One B-rep face of a CAD part: STEP entity #1449.
In plain terms, the planar face has unit normal (0, 1, 0).
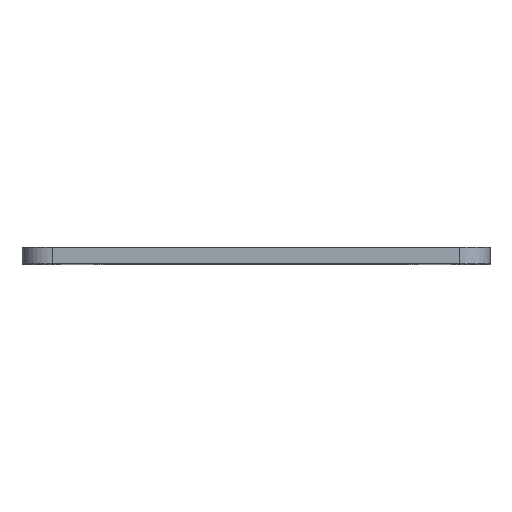
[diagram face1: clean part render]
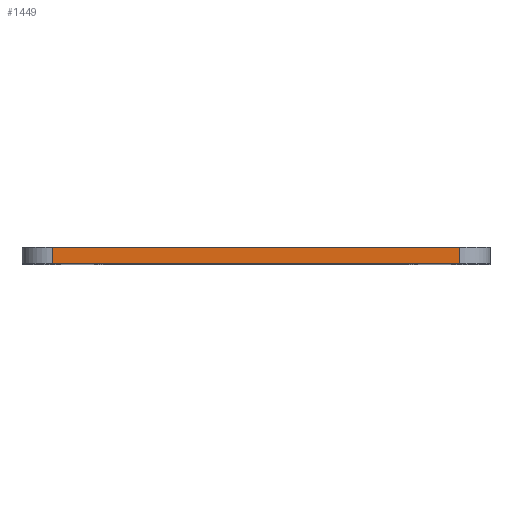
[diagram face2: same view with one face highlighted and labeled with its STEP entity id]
Its self-contained STEP definition (entity closure, numbers rounded to 3 decimals):
#62 = PLANE('',#63);
#63 = AXIS2_PLACEMENT_3D('',#64,#65,#66);
#64 = CARTESIAN_POINT('',(0.,14.5,-1.2));
#65 = DIRECTION('',(0.,0.,1.));
#66 = DIRECTION('',(1.,0.,-0.));
#118 = PLANE('',#119);
#119 = AXIS2_PLACEMENT_3D('',#120,#121,#122);
#120 = CARTESIAN_POINT('',(0.,14.5,0.));
#121 = DIRECTION('',(0.,0.,1.));
#122 = DIRECTION('',(1.,0.,-0.));
#385 = VERTEX_POINT('',#386);
#386 = CARTESIAN_POINT('',(14.8,30.,-1.2));
#405 = CYLINDRICAL_SURFACE('',#406,2.2);
#406 = AXIS2_PLACEMENT_3D('',#407,#408,#409);
#407 = CARTESIAN_POINT('',(14.8,27.8,-1.2));
#408 = DIRECTION('',(0.,0.,-1.));
#409 = DIRECTION('',(-1.,0.,0.));
#417 = EDGE_CURVE('',#418,#385,#420,.T.);
#418 = VERTEX_POINT('',#419);
#419 = CARTESIAN_POINT('',(-14.8,30.,-1.2));
#420 = SURFACE_CURVE('',#421,(#425,#432),.PCURVE_S1.);
#421 = LINE('',#422,#423);
#422 = CARTESIAN_POINT('',(0.,30.,-1.2));
#423 = VECTOR('',#424,1.);
#424 = DIRECTION('',(1.,0.,0.));
#425 = PCURVE('',#62,#426);
#426 = DEFINITIONAL_REPRESENTATION('',(#427),#431);
#427 = LINE('',#428,#429);
#428 = CARTESIAN_POINT('',(0.,15.5));
#429 = VECTOR('',#430,1.);
#430 = DIRECTION('',(1.,0.));
#431 = ( GEOMETRIC_REPRESENTATION_CONTEXT(2) 
PARAMETRIC_REPRESENTATION_CONTEXT() REPRESENTATION_CONTEXT('2D SPACE',''
  ) );
#432 = PCURVE('',#433,#438);
#433 = PLANE('',#434);
#434 = AXIS2_PLACEMENT_3D('',#435,#436,#437);
#435 = CARTESIAN_POINT('',(-14.8,30.,-1.2));
#436 = DIRECTION('',(0.,1.,0.));
#437 = DIRECTION('',(1.,0.,0.));
#438 = DEFINITIONAL_REPRESENTATION('',(#439),#443);
#439 = LINE('',#440,#441);
#440 = CARTESIAN_POINT('',(14.8,0.));
#441 = VECTOR('',#442,1.);
#442 = DIRECTION('',(1.,0.));
#443 = ( GEOMETRIC_REPRESENTATION_CONTEXT(2) 
PARAMETRIC_REPRESENTATION_CONTEXT() REPRESENTATION_CONTEXT('2D SPACE',''
  ) );
#466 = CYLINDRICAL_SURFACE('',#467,2.2);
#467 = AXIS2_PLACEMENT_3D('',#468,#469,#470);
#468 = CARTESIAN_POINT('',(-14.8,27.8,-1.2));
#469 = DIRECTION('',(0.,0.,-1.));
#470 = DIRECTION('',(-1.,0.,0.));
#1069 = VERTEX_POINT('',#1070);
#1070 = CARTESIAN_POINT('',(14.8,30.,0.));
#1096 = EDGE_CURVE('',#1097,#1069,#1099,.T.);
#1097 = VERTEX_POINT('',#1098);
#1098 = CARTESIAN_POINT('',(-14.8,30.,0.));
#1099 = SURFACE_CURVE('',#1100,(#1104,#1111),.PCURVE_S1.);
#1100 = LINE('',#1101,#1102);
#1101 = CARTESIAN_POINT('',(0.,30.,0.));
#1102 = VECTOR('',#1103,1.);
#1103 = DIRECTION('',(1.,0.,0.));
#1104 = PCURVE('',#118,#1105);
#1105 = DEFINITIONAL_REPRESENTATION('',(#1106),#1110);
#1106 = LINE('',#1107,#1108);
#1107 = CARTESIAN_POINT('',(0.,15.5));
#1108 = VECTOR('',#1109,1.);
#1109 = DIRECTION('',(1.,0.));
#1110 = ( GEOMETRIC_REPRESENTATION_CONTEXT(2) 
PARAMETRIC_REPRESENTATION_CONTEXT() REPRESENTATION_CONTEXT('2D SPACE',''
  ) );
#1111 = PCURVE('',#433,#1112);
#1112 = DEFINITIONAL_REPRESENTATION('',(#1113),#1117);
#1113 = LINE('',#1114,#1115);
#1114 = CARTESIAN_POINT('',(14.8,-1.2));
#1115 = VECTOR('',#1116,1.);
#1116 = DIRECTION('',(1.,0.));
#1117 = ( GEOMETRIC_REPRESENTATION_CONTEXT(2) 
PARAMETRIC_REPRESENTATION_CONTEXT() REPRESENTATION_CONTEXT('2D SPACE',''
  ) );
#1428 = EDGE_CURVE('',#418,#1097,#1429,.T.);
#1429 = SURFACE_CURVE('',#1430,(#1434,#1441),.PCURVE_S1.);
#1430 = LINE('',#1431,#1432);
#1431 = CARTESIAN_POINT('',(-14.8,30.,-1.2));
#1432 = VECTOR('',#1433,1.);
#1433 = DIRECTION('',(0.,0.,1.));
#1434 = PCURVE('',#466,#1435);
#1435 = DEFINITIONAL_REPRESENTATION('',(#1436),#1440);
#1436 = LINE('',#1437,#1438);
#1437 = CARTESIAN_POINT('',(1.571,0.));
#1438 = VECTOR('',#1439,1.);
#1439 = DIRECTION('',(0.,-1.));
#1440 = ( GEOMETRIC_REPRESENTATION_CONTEXT(2) 
PARAMETRIC_REPRESENTATION_CONTEXT() REPRESENTATION_CONTEXT('2D SPACE',''
  ) );
#1441 = PCURVE('',#433,#1442);
#1442 = DEFINITIONAL_REPRESENTATION('',(#1443),#1447);
#1443 = LINE('',#1444,#1445);
#1444 = CARTESIAN_POINT('',(0.,0.));
#1445 = VECTOR('',#1446,1.);
#1446 = DIRECTION('',(0.,-1.));
#1447 = ( GEOMETRIC_REPRESENTATION_CONTEXT(2) 
PARAMETRIC_REPRESENTATION_CONTEXT() REPRESENTATION_CONTEXT('2D SPACE',''
  ) );
#1449 = ADVANCED_FACE('',(#1450),#433,.T.);
#1450 = FACE_BOUND('',#1451,.T.);
#1451 = EDGE_LOOP('',(#1452,#1453,#1454,#1475));
#1452 = ORIENTED_EDGE('',*,*,#1428,.T.);
#1453 = ORIENTED_EDGE('',*,*,#1096,.T.);
#1454 = ORIENTED_EDGE('',*,*,#1455,.F.);
#1455 = EDGE_CURVE('',#385,#1069,#1456,.T.);
#1456 = SURFACE_CURVE('',#1457,(#1461,#1468),.PCURVE_S1.);
#1457 = LINE('',#1458,#1459);
#1458 = CARTESIAN_POINT('',(14.8,30.,-1.2));
#1459 = VECTOR('',#1460,1.);
#1460 = DIRECTION('',(0.,0.,1.));
#1461 = PCURVE('',#433,#1462);
#1462 = DEFINITIONAL_REPRESENTATION('',(#1463),#1467);
#1463 = LINE('',#1464,#1465);
#1464 = CARTESIAN_POINT('',(29.6,0.));
#1465 = VECTOR('',#1466,1.);
#1466 = DIRECTION('',(0.,-1.));
#1467 = ( GEOMETRIC_REPRESENTATION_CONTEXT(2) 
PARAMETRIC_REPRESENTATION_CONTEXT() REPRESENTATION_CONTEXT('2D SPACE',''
  ) );
#1468 = PCURVE('',#405,#1469);
#1469 = DEFINITIONAL_REPRESENTATION('',(#1470),#1474);
#1470 = LINE('',#1471,#1472);
#1471 = CARTESIAN_POINT('',(1.571,0.));
#1472 = VECTOR('',#1473,1.);
#1473 = DIRECTION('',(0.,-1.));
#1474 = ( GEOMETRIC_REPRESENTATION_CONTEXT(2) 
PARAMETRIC_REPRESENTATION_CONTEXT() REPRESENTATION_CONTEXT('2D SPACE',''
  ) );
#1475 = ORIENTED_EDGE('',*,*,#417,.F.);
